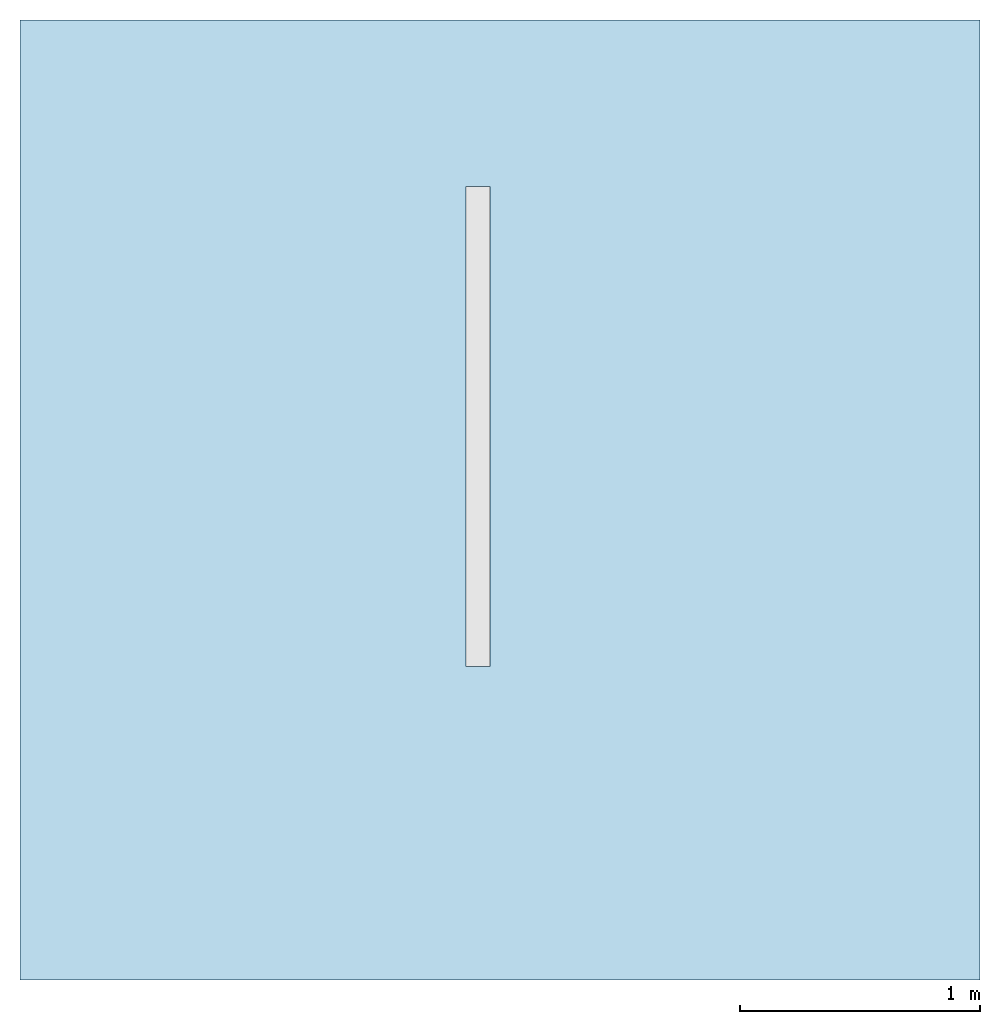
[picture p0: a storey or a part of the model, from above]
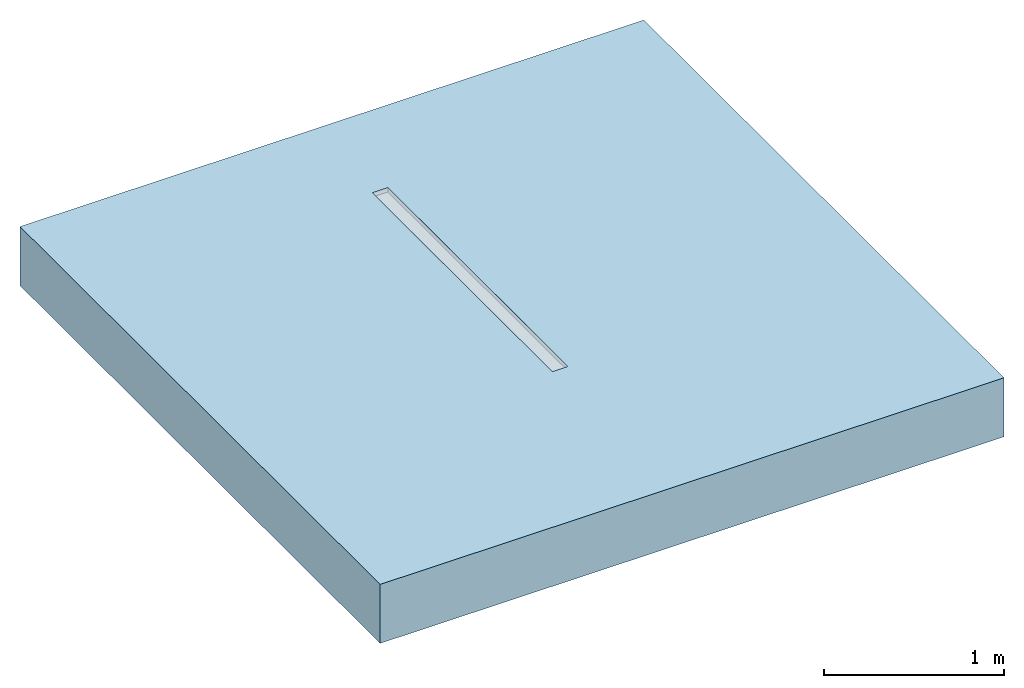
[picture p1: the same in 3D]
Properties of the parts of a building model (IFC2X3)

# File
Description: ViewDefinition [CoordinationView]
File name: Project Number
Time: 2014-06-06T10:58:19
Written by: The EXPRESS Data Manager Version 5.01.0100.02.64mod : 6 Jun 2012
Made in: 20130308_1515(x64) - Exporter 2014.0.2013.0308 - Default UI
Comment: STEP Physical File produced by: The EXPRESS Data Manager Version 5.01.0100.02.64mod : 6 Jun 2012 * Module: EDMstepFileFactory/EDMstandAlone * Creation date: Fri Jun 06 10:58:19 2014 * Host: IN-BLR-PC-0010 * Database: C:\Users\palleri\AppData\Local\Temp\{DE9E7067-3A92-44B8-9F56-0CE2671AD995}\ifc * Database version: 5507 * Database creation date: Fri Jun 06 10:58:18 2014 * Schema: IFC2X3 * Model: DataRepository.ifc * Model creation date: Fri Jun 06 10:58:19 2014 * Header model: DataRepository.ifc_HeaderModel * Header model creation date: Fri Jun 06 10:58:19 2014 * EDMuser: sdai-user * EDMgroup: sdai-group * License ID and type: 5605 : Permanent license. Expiry date: * EDMstepFileFactory options: 020000

# IfcProject, Project Number
LongName: Project Name; Phase: Project Status

# IfcSite, Default
RefLatitude: 42, 21, 30, 344238; RefLongitude: -71, -3, -35, -194702; RefElevation: 0 mm

# IfcBuilding
Pset_BuildingCommon - NumberOfStoreys: 1
Other - Project Address: ## Street City, State Zip; Project Issue Date: Issue Date; Project Name: Project Name; Project Number: Project Number; Client Name: Owner; Project Status: Project Status

# IfcBuildingStorey, Level 1
LongName: Level 1; Elevation: 0 mm
Constraints - Elevation Base: Project Base Point; Elevation: 0 mm
Graphics - Color: 0; Line Weight: 1; Line Pattern: Center; Symbol at End 2 Default: yes; Symbol at End 1 Default: no; Symbol: M_Level Head - Circle: M_Level Head - Circle
Identity Data - Structural: no; Building Story: yes; Name: Level 1
Dimensions - Computation Height: 0 mm

# IfcFlowTerminal: 00328 - Drainage Duct - 2000mm LG, ACO Freedeck Access Frame & Drain Duct (Accessories part 1) V1.27 - GS:00328 - Drainage Duct - 2000mm LG:276243
In: Level 1
Material: Galvanized Steel
Identity Data - Mark: 14; Website: www.acobd.com; Watermarked With: BIM Manager Premium Suite; Watermarked By: www.acobd.com; Manufacturer: ACO Building Drainage; Fax: +44 (0)1462 851490; Watermark1: This file is the property of ACO Technologies PLC; Address: ACO Business Centre, Caxton Road, Bedford, MK41 0LF; E-mail Sales: abdcommercial@aco.co.uk; Telephone: +44 (0)1462 816666; E-mail Technical: abdtechnical@aco.co.uk; Watermark2: This file is water marked and users are prohibited to reproduce, adapt, distribute this information
Constraints - Level: Level: Level 1; Moves With Nearby Elements: no
Dimensions - Top Void Height Start: 2 mm; Access Frame Extension Position Height: 5000 mm; Base Height: 3000 mm; Top Void Height End: 0 mm; Height for Adjustable Access Frame: 105 mm; Drainage Duct – Level below FFL: 30 mm; Total Height: 105 mm; Grating Start: 0 mm; Grating End: -20 mm; Drain Duct End: -2000 mm
Other - Access Frame Extension: no; Adjustable Access Frame Position Height: 105 mm; Drain Duct Vertical Height: 30 mm; Access Frame Extension Height: 50 mm; Extension Removal Void: 400 mm; Fixed Access Frame Position Height: 50 mm; Access Frame Extension_Invert Depth 50mm: no; Access Frame Extension_Invert Depth 75mm: no; Top void Size: 397 mm; Drain Duct: yes; Grating: no; Access Frame Fixed Height: no; Access Frame Adjustable Height: no
Construction - 38685_Access Frame Extension_Galvanized Steel_Invert Depth 50mm: no; 38687_Access Frame Extension_Galvanized Steel_Invert Depth 75mm: no; 36754_Access Grating_Mesh Grating_Galvanized Steel: no
Phasing - Phase Created: New Construction
Pset_ManufacturerTypeInformation - Manufacturer: ACO Building Drainage
General - Installation Guidelines: X:\Electronic Literature\ABD Electronic Literature\Roof and Balcony Drainage\ACO Freedeck Brochure.pdf; Product Description: ACO Freedeck Drainage Duct; Product Standard: BS EN 1433:2002, CE marked; Product Type: Linear Deck Drainage System; Weight (Kg): 2.4kg; Channel Recycled Material Content: 25 - 30 %; Product Code: 00328; Maintenance Guidelines: X:\Electronic Literature\ABD Electronic Literature\Roof and Balcony Drainage\ACO Freedeck Brochure.pdf; NBS Specification: NBS Section R10 Gravity Rainwater Drainage Systems, Subsection 365; Product Range: ACO Freedeck; Dimensions (LxWxH): 100 x 30 x 2000; Channel Colour: Galvanised; Price: POA - contact ACO; Channel Material: Hot Dipped Galvanised Steel; Load Class: A15; Channel Recyclable: Fully recyclable
Materials and Finishes - Material: Galvanized Steel
Model Properties - Access Grating Product Code 36754: Load Class A15 - Mesh Grating - 14mm x 30mm Mesh - Galvanized Steel - 3.5kg; Access Frame Extension Product Code 38685: Load Class A15 - Access Frame Extension - Galvanized Steel - Invert Depth 50mm - 1.3kg; Access Frame Extension Product Code 38687: Load Class A15 - Access Frame Extension - Galvanized Steel - Invert Depth 75mm - 1.9kg; Access Grating Product Code 36760: N/A; Access Frame Extension Product Code 38686: N/A; Access Frame Extension Product Code 38688: N/A

# IfcSlab: Floor:Generic Floor - 400mm, Floor:Generic Floor - 400mm:193825
In: Level 1
PredefinedType: FLOOR; Material: Concrete, Broom Finish 400 mm
Dimensions - Area: 16 m2; Thickness: 400 mm; Perimeter: 16000 mm; Volume: 6.394 m3
Phasing - Phase Created: New Construction
Constraints - Level: Level: Level 1; Room Bounding: yes; Related to Mass: no; Height Offset From Level: 0 mm
Structural - Structural: no; Enable Analytical Model: no
Pset_SlabCommon - Reference: Generic Floor - 400mm; IsExternal: no; LoadBearing: yes; ThermalTransmittance: 2.615 kg/K/s3; PitchAngle: 0 deg
Graphics - Coarse Scale Fill Color: 0
Analytical Properties - Thermal mass: 604440; Absorptance: 0.1; Thermal Resistance (R): 0.382409; Heat Transfer Coefficient (U): 2.615; Roughness: 1
Construction - Default Thickness: 400 mm; Function: Interior
Materials and Finishes - Structural Material: Concrete, Broom Finish
